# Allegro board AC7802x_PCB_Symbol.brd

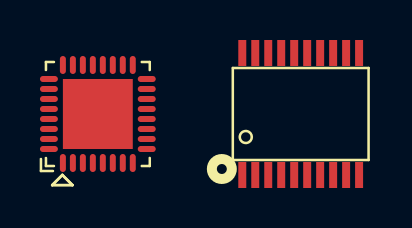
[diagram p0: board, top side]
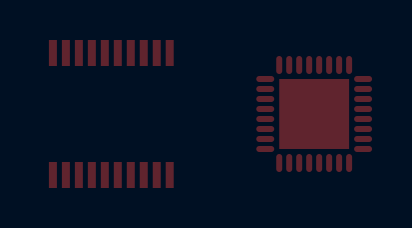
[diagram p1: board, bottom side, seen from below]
No outline. copper layers: TOP, BOTTOM. Coordinates in mm from the lowest, leftmost part position.

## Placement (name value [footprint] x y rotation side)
U1  -  [AC7802_HVQFN32_SMD_P0_5_5X5]  0 0 0 top
U3  -  [AC7802_TSSOP20_SMD_P0_65_6_5X4_4]  10.16 0 0 top

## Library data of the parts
U1 = AC7802_HVQFN32_SMD_P0_5_5X5
U3 = AC7802_TSSOP20_SMD_P0_65_6_5X4_4

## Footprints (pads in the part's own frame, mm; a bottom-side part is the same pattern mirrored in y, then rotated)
AC7802_HVQFN32_SMD_P0_5_5X5
  oval 0.3x0.9 smd: 1(-1.75,-2.45) 2(-1.25,-2.45) 3(-0.75,-2.45) 4(-0.25,-2.45) 5(0.25,-2.45) 6(0.75,-2.45) 7(1.25,-2.45) 8(1.75,-2.45) 17(1.75,2.45) 18(1.25,2.45) 19(0.75,2.45) 20(0.25,2.45) 21(-0.25,2.45) 22(-0.75,2.45) 23(-1.25,2.45) 24(-1.75,2.45)
  oval 0.9x0.3 smd: 9(2.45,-1.75) 10(2.45,-1.25) 11(2.45,-0.75) 12(2.45,-0.25) 13(2.45,0.25) 14(2.45,0.75) 15(2.45,1.25) 16(2.45,1.75) 25(-2.45,1.75) 26(-2.45,1.25) 27(-2.45,0.75) 28(-2.45,0.25) 29(-2.45,-0.25) 30(-2.45,-0.75) 31(-2.45,-1.25) 32(-2.45,-1.75)
  rect 3.5x3.5 smd: 33(0,0)
AC7802_TSSOP20_SMD_P0_65_6_5X4_4
  rect 0.4x1.3 smd: 1(-2.925,-3.05) 2(-2.275,-3.05) 3(-1.625,-3.05) 4(-0.975,-3.05) 5(-0.325,-3.05) 6(0.325,-3.05) 7(0.975,-3.05) 8(1.625,-3.05) 9(2.275,-3.05) 10(2.925,-3.05) 11(2.925,3.05) 12(2.275,3.05) 13(1.625,3.05) 14(0.975,3.05) 15(0.325,3.05) 16(-0.325,3.05) 17(-0.975,3.05) 18(-1.625,3.05) 19(-2.275,3.05) 20(-2.925,3.05)

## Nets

Pads without a net: U1 1 2 3 4 5 6 7 8 9 10 11 12 13 14 15 16 17 18 19 20 21 22 23 24 25 26 27 28 29 30 31 32 33; U3 1 2 3 4 5 6 7 8 9 10 11 12 13 14 15 16 17 18 19 20
